VERSION 5.4 ;
NAMESCASESENSITIVE ON ;
BUSBITCHARS "[]" ;
DIVIDERCHAR "/" ;
UNITS
  DATABASE MICRONS 2000 ;
END UNITS
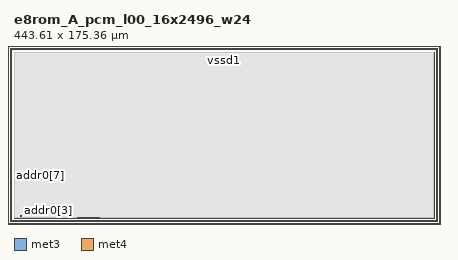
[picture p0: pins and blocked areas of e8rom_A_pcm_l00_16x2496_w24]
MACRO e8rom_A_pcm_l00_16x2496_w24
   CLASS BLOCK ;
   SIZE 443.61 BY 175.36 ;
   SYMMETRY X Y R90 ;
   PIN clk0
      DIRECTION INPUT ;
      PORT
         LAYER met3 ;
         RECT  -9.65 11.355 -9.16 11.845 ;
      END
   END clk0
   PIN cs0
      DIRECTION INPUT ;
      PORT
         LAYER met3 ;
         RECT  7.03 1.98 7.52 2.47 ;
      END
   END cs0
   PIN addr0[0]
      DIRECTION INPUT ;
      PORT
         LAYER met3 ;
         RECT  30.095 1.39 30.585 1.88 ;
      END
   END addr0[0]
   PIN addr0[1]
      DIRECTION INPUT ;
      PORT
         LAYER met3 ;
         RECT  32.135 1.39 32.625 1.88 ;
      END
   END addr0[1]
   PIN addr0[2]
      DIRECTION INPUT ;
      PORT
         LAYER met3 ;
         RECT  34.175 1.39 34.665 1.88 ;
      END
   END addr0[2]
   PIN addr0[3]
      DIRECTION INPUT ;
      PORT
         LAYER met3 ;
         RECT  36.215 1.39 36.705 1.88 ;
      END
   END addr0[3]
   PIN addr0[4]
      DIRECTION INPUT ;
      PORT
         LAYER met3 ;
         RECT  38.255 1.39 38.745 1.88 ;
      END
   END addr0[4]
   PIN addr0[5]
      DIRECTION INPUT ;
      PORT
         LAYER met3 ;
         RECT  1.525 45.055 2.015 45.545 ;
      END
   END addr0[5]
   PIN addr0[6]
      DIRECTION INPUT ;
      PORT
         LAYER met3 ;
         RECT  3.565 45.055 4.055 45.545 ;
      END
   END addr0[6]
   PIN addr0[7]
      DIRECTION INPUT ;
      PORT
         LAYER met3 ;
         RECT  5.605 45.055 6.095 45.545 ;
      END
   END addr0[7]
   PIN addr0[8]
      DIRECTION INPUT ;
      PORT
         LAYER met3 ;
         RECT  7.645 45.055 8.135 45.545 ;
      END
   END addr0[8]
   PIN addr0[9]
      DIRECTION INPUT ;
      PORT
         LAYER met3 ;
         RECT  9.685 45.055 10.175 45.545 ;
      END
   END addr0[9]
   PIN addr0[10]
      DIRECTION INPUT ;
      PORT
         LAYER met3 ;
         RECT  11.725 45.055 12.215 45.545 ;
      END
   END addr0[10]
   PIN addr0[11]
      DIRECTION INPUT ;
      PORT
         LAYER met3 ;
         RECT  13.765 45.055 14.255 45.545 ;
      END
   END addr0[11]
   PIN dout0[0]
      DIRECTION OUTPUT ;
      PORT
         LAYER met3 ;
         RECT  67.14 -0.16 67.63 0.33 ;
      END
   END dout0[0]
   PIN dout0[1]
      DIRECTION OUTPUT ;
      PORT
         LAYER met3 ;
         RECT  68.68 -0.16 69.17 0.33 ;
      END
   END dout0[1]
   PIN dout0[2]
      DIRECTION OUTPUT ;
      PORT
         LAYER met3 ;
         RECT  70.22 -0.16 70.71 0.33 ;
      END
   END dout0[2]
   PIN dout0[3]
      DIRECTION OUTPUT ;
      PORT
         LAYER met3 ;
         RECT  71.76 -0.16 72.25 0.33 ;
      END
   END dout0[3]
   PIN dout0[4]
      DIRECTION OUTPUT ;
      PORT
         LAYER met3 ;
         RECT  73.3 -0.16 73.79 0.33 ;
      END
   END dout0[4]
   PIN dout0[5]
      DIRECTION OUTPUT ;
      PORT
         LAYER met3 ;
         RECT  74.84 -0.16 75.33 0.33 ;
      END
   END dout0[5]
   PIN dout0[6]
      DIRECTION OUTPUT ;
      PORT
         LAYER met3 ;
         RECT  76.38 -0.16 76.87 0.33 ;
      END
   END dout0[6]
   PIN dout0[7]
      DIRECTION OUTPUT ;
      PORT
         LAYER met3 ;
         RECT  77.92 -0.16 78.41 0.33 ;
      END
   END dout0[7]
   PIN dout0[8]
      DIRECTION OUTPUT ;
      PORT
         LAYER met3 ;
         RECT  79.46 -0.16 79.95 0.33 ;
      END
   END dout0[8]
   PIN dout0[9]
      DIRECTION OUTPUT ;
      PORT
         LAYER met3 ;
         RECT  81.0 -0.16 81.49 0.33 ;
      END
   END dout0[9]
   PIN dout0[10]
      DIRECTION OUTPUT ;
      PORT
         LAYER met3 ;
         RECT  82.54 -0.16 83.03 0.33 ;
      END
   END dout0[10]
   PIN dout0[11]
      DIRECTION OUTPUT ;
      PORT
         LAYER met3 ;
         RECT  84.08 -0.16 84.57 0.33 ;
      END
   END dout0[11]
   PIN dout0[12]
      DIRECTION OUTPUT ;
      PORT
         LAYER met3 ;
         RECT  85.62 -0.16 86.11 0.33 ;
      END
   END dout0[12]
   PIN dout0[13]
      DIRECTION OUTPUT ;
      PORT
         LAYER met3 ;
         RECT  87.16 -0.16 87.65 0.33 ;
      END
   END dout0[13]
   PIN dout0[14]
      DIRECTION OUTPUT ;
      PORT
         LAYER met3 ;
         RECT  88.7 -0.16 89.19 0.33 ;
      END
   END dout0[14]
   PIN dout0[15]
      DIRECTION OUTPUT ;
      PORT
         LAYER met3 ;
         RECT  90.24 -0.16 90.73 0.33 ;
      END
   END dout0[15]
   PIN vccd1
      DIRECTION INOUT ;
      USE POWER ; 
      SHAPE ABUTMENT ; 
      PORT
         LAYER met4 ;
         RECT  -7.48 -7.48 -5.74 182.84 ;
         LAYER met3 ;
         RECT  -7.48 181.1 451.09 182.84 ;
         LAYER met4 ;
         RECT  449.35 -7.48 451.09 182.84 ;
         LAYER met3 ;
         RECT  -7.48 -7.48 451.09 -5.74 ;
      END
   END vccd1
   PIN vssd1
      DIRECTION INOUT ;
      USE GROUND ; 
      SHAPE ABUTMENT ; 
      PORT
         LAYER met3 ;
         RECT  -4.0 177.62 447.61 179.36 ;
         LAYER met4 ;
         RECT  -4.0 -4.0 -2.26 179.36 ;
         LAYER met3 ;
         RECT  -4.0 -4.0 447.61 -2.26 ;
         LAYER met4 ;
         RECT  445.87 -4.0 447.61 179.36 ;
      END
   END vssd1
   OBS
   LAYER  met1 ;
      RECT  0.62 0.62 442.99 174.74 ;
   LAYER  met2 ;
      RECT  0.62 0.62 442.99 174.74 ;
   LAYER  met3 ;
      RECT  0.62 0.62 6.43 1.38 ;
      RECT  0.62 1.38 6.43 3.07 ;
      RECT  6.43 0.62 8.12 1.38 ;
      RECT  8.12 0.62 29.495 0.79 ;
      RECT  8.12 0.79 29.495 1.38 ;
      RECT  29.495 0.62 31.185 0.79 ;
      RECT  8.12 1.38 29.495 2.48 ;
      RECT  8.12 2.48 29.495 3.07 ;
      RECT  29.495 2.48 31.185 3.07 ;
      RECT  31.185 2.48 442.99 3.07 ;
      RECT  31.185 0.79 31.535 1.38 ;
      RECT  31.185 1.38 31.535 2.48 ;
      RECT  33.225 0.79 33.575 1.38 ;
      RECT  33.225 1.38 33.575 2.48 ;
      RECT  35.265 0.79 35.615 1.38 ;
      RECT  35.265 1.38 35.615 2.48 ;
      RECT  37.305 0.79 37.655 1.38 ;
      RECT  37.305 1.38 37.655 2.48 ;
      RECT  39.345 1.38 442.99 2.48 ;
      RECT  0.62 3.07 0.925 44.455 ;
      RECT  0.62 44.455 0.925 46.145 ;
      RECT  0.62 46.145 0.925 174.74 ;
      RECT  0.925 3.07 2.615 44.455 ;
      RECT  0.925 46.145 2.615 174.74 ;
      RECT  2.615 3.07 6.43 44.455 ;
      RECT  2.615 46.145 6.43 174.74 ;
      RECT  2.615 44.455 2.965 46.145 ;
      RECT  6.43 3.07 6.695 44.455 ;
      RECT  6.43 46.145 6.695 174.74 ;
      RECT  6.695 3.07 8.12 44.455 ;
      RECT  6.695 46.145 8.12 174.74 ;
      RECT  4.655 44.455 5.005 46.145 ;
      RECT  8.12 3.07 8.735 44.455 ;
      RECT  8.12 46.145 8.735 174.74 ;
      RECT  8.735 3.07 442.99 44.455 ;
      RECT  8.735 46.145 442.99 174.74 ;
      RECT  6.695 44.455 7.045 46.145 ;
      RECT  8.735 44.455 9.085 46.145 ;
      RECT  10.775 44.455 11.125 46.145 ;
      RECT  12.815 44.455 13.165 46.145 ;
      RECT  14.855 44.455 442.99 46.145 ;
      RECT  31.185 0.62 66.54 0.79 ;
      RECT  39.345 0.79 66.54 0.93 ;
      RECT  39.345 0.93 66.54 1.38 ;
      RECT  66.54 0.93 68.23 1.38 ;
      RECT  68.23 0.93 442.99 1.38 ;
      RECT  91.33 0.62 442.99 0.79 ;
      RECT  91.33 0.79 442.99 0.93 ;
   LAYER  met4 ;
      RECT  0.62 0.62 442.99 174.74 ;
   END
END    e8rom_A_pcm_l00_16x2496_w24
END    LIBRARY
